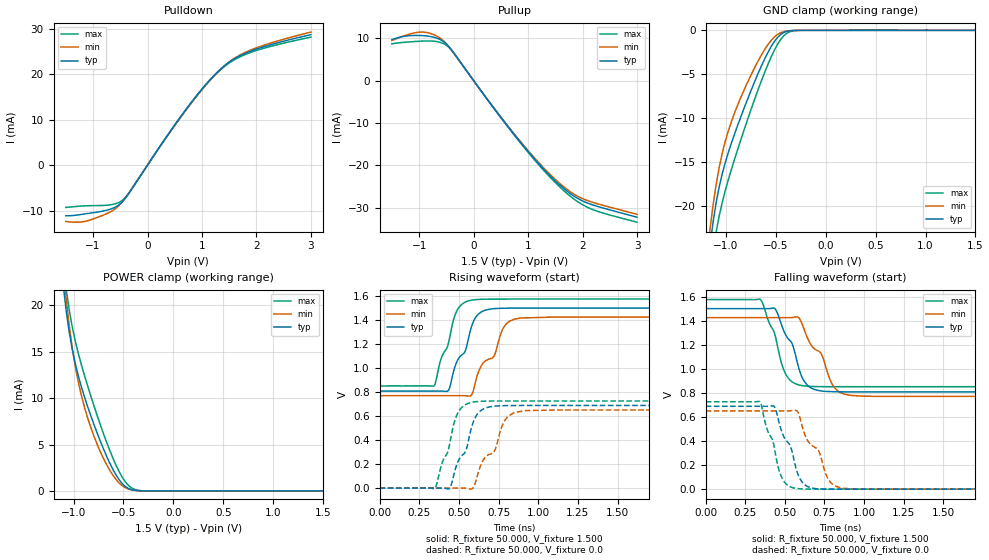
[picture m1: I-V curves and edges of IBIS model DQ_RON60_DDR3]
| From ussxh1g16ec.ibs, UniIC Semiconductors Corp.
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|   Model DQ_RON60_DDR3
[Model] DQ_RON60_DDR3
Model_type I/O
Vinl =  0.615V
Vinh =  0.885V
Vmeas =  0.750V
Rref =  50.000
Vref =  0.750V
C_comp   1.232pF   1.219pF   1.235pF
[Model Spec]
Vinh   0.885V   0.847V   0.922V
Vinl   0.615V   0.577V   0.652V
Vmeas   0.750V   0.712V   0.787V
Vref   0.750V   0.712V   0.787V
Rref   50.000   NA   NA
[Temperature Range]   25.000   95.000   0.0
[Voltage Range]   1.500V   1.425V   1.575V
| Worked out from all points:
|   slope of the pulldown table from 0 to 0.225 V, typ, clamps not added: 55.6 ohm
|   slope of the pullup table from 0 to 0.225 V, typ, clamps not added: 56.8 ohm
|   GND clamp passes 1 mA (typ) near -0.49 V on its own axis
|   POWER clamp passes 1 mA (typ) near -0.53 V on its own axis
|   rising waveform, R_fixture 50.000, V_fixture 1.500: 20-80 % time 122ps typ, 159ps min, 101ps max; typ from 0.808 V to 1.5 V
|   rising waveform, R_fixture 50.000, V_fixture 0.0: 20-80 % time 117ps typ, 151ps min, 98.5ps max; typ from 0 V to 0.688 V
|   falling waveform, R_fixture 50.000, V_fixture 1.500: 20-80 % time 123ps typ, 157ps min, 104ps max; typ from 1.5 V to 0.808 V
|   falling waveform, R_fixture 50.000, V_fixture 0.0: 20-80 % time 115ps typ, 148ps min, 95.5ps max; typ from 0.688 V to 0 V
[Pulldown]
|Voltage   I(typ)   I(min)   I(max)
-1.5V     -11.15mA   -12.39mA   -9.29mA
-1.224V   -10.85mA   -12.51mA   -9.004mA
-948mV    -10.37mA   -11.62mA   -8.896mA
-626mV    -9.419mA   -9.874mA   -8.605mA
-442mV    -7.812mA   -7.785mA   -7.561mA
-304mV    -5.522mA   -5.433mA   -5.531mA
340mV     6.066mA    5.969mA    6.085mA
800mV     13.71mA    13.56mA    13.69mA
1.168V    19.03mA    18.93mA    18.92mA
1.49V     22.55mA    22.6mA     22.35mA
1.996V    25.49mA    25.77mA    25.19mA
3V        28.67mA    29.24mA    28.12mA
[Pullup]
|Voltage   I(typ)   I(min)   I(max)
-1.5V     9.689mA    9.449mA    8.684mA
-1.14V    10.61mA    11.09mA    9.161mA
-910mV    10.58mA    11.42mA    9.33mA
-680mV    10.03mA    10.53mA    9.208mA
-496mV    8.577mA    8.63mA     8.283mA
-358mV    6.405mA    6.362mA    6.41mA
746mV     -12.72mA   -12.56mA   -12.85mA
1.16V     -19.08mA   -18.83mA   -19.32mA
1.528V    -23.99mA   -23.63mA   -24.4mA
1.804V    -26.9mA    -26.45mA   -27.55mA
2.08V     -28.81mA   -28.23mA   -29.79mA
3V        -32.21mA   -31.53mA   -33.38mA
[GND_clamp]
|Voltage   I(typ)   I(min)   I(max)
-1.5V     -77.15mA   -73.99mA   -82.95mA
-1.159V   -24.58mA   -22.75mA   -28.09mA
-1.128V   -21.88mA   -19.96mA   -25.29mA
-1.097V   -19.64mA   -17.59mA   -23mA
-1.066V   -17.82mA   -15.61mA   -21.13mA
-1.004V   -15mA      -12.58mA   -18.19mA
-880mV    -10.79mA   -8.48mA    -13.52mA
-632mV    -3.776mA   -2.594mA   -5.41mA
-477mV    -756.2uA   -431.9uA   -1.507mA
-384mV    -106.6uA   -66.16uA   -298.8uA
-291mV    -7.441uA   -6.674uA   -23.65uA
1.5V      0A         0A         0A
[POWER_clamp]
|Voltage   I(typ)   I(min)   I(max)
-1.5V     91.1mA     92.64mA    94.45mA
-1.104V   22.28mA    23.97mA    24.53mA
-1.073V   19.41mA    20.63mA    21.7mA
-1.042V   17.07mA    17.76mA    19.43mA
-980mV    13.62mA    13.3mA     16.05mA
-918mV    11.11mA    10.16mA    13.48mA
-856mV    9.013mA    7.787mA    11.23mA
-670mV    3.78mA     2.864mA    5.289mA
-577mV    1.775mA    1.269mA    2.836mA
-484mV    502.3uA    362.1uA    1.023mA
-298mV    5.274uA    7.672uA    13.48uA
1.5V      0A         0A         0A
[Ramp]
| variable   typ   min   max
dV/dt_r   0.413/0.117n   0.390/0.151n   0.436/98.657p
dV/dt_f   0.415/0.123n   0.393/0.157n   0.434/0.104n
R_load = 50.000
[Rising Waveform]
R_fixture= 50.000
V_fixture= 1.500
V_fixture_min= 1.425
V_fixture_max= 1.575
|time   V(typ)   V(min)   V(max)
0s        808mV      770.4mV    851.1mV
342ps     808.1mV    770.4mV    851.2mV
436ps     818.5mV    770.4mV    1.221V
489ps     1.059V     770.5mV    1.483V
539ps     1.14V      769.7mV    1.549V
576ps     1.331V     771.7mV    1.565V
653ps     1.476V     1.043V     1.574V
722ps     1.495V     1.101V     1.575V
848ps     1.5V       1.407V     1.575V
3ns       1.5V       1.425V     1.575V
[Rising Waveform]
R_fixture= 50.000
V_fixture= 0.0
V_fixture_min= 0.0
V_fixture_max= 0.0
|time   V(typ)   V(min)   V(max)
0s        174.5nV    711.1nV    276.3nV
346ps     -21.92uV   10.29uV    -5.042mV
442ps     220.1uV    -12.14uV   371.2mV
498ps     233.1mV    204.9uV    638mV
546ps     320.6mV    -543.7uV   699.2mV
586ps     534.9mV    -3.305mV   715.8mV
662ps     664.4mV    251mV      724.3mV
718ps     681.6mV    295.6mV    725.5mV
850ps     688mV      630mV      725.8mV
3ns       688.4mV    650.7mV    725.9mV
[Falling Waveform]
R_fixture= 50.000
V_fixture= 1.500
V_fixture_min= 1.425
V_fixture_max= 1.575
|time   V(typ)   V(min)   V(max)
0s        1.5V       1.425V     1.575V
344ps     1.5V       1.425V     1.577V
445ps     1.485V     1.425V     1.24V
511ps     1.267V     1.425V     942.3mV
552ps     1.187V     1.427V     885.8mV
603ps     946.2mV    1.391V     861.6mV
730ps     815.9mV    1.125V     851.7mV
797ps     809.9mV    875.8mV    851.3mV
882ps     808.3mV    787.1mV    851.2mV
3ns       808mV      770.4mV    851.2mV
[Falling Waveform]
R_fixture= 50.000
V_fixture= 0.0
V_fixture_min= 0.0
V_fixture_max= 0.0
|time   V(typ)   V(min)   V(max)
0s        688.4mV    650.7mV    725.9mV
341ps     688.4mV    650.6mV    727.1mV
434ps     684.7mV    650.6mV    339.9mV
481ps     472.5mV    650.5mV    94.12mV
561ps     222mV      654.8mV    8.52mV
644ps     20.98mV    402.3mV    691.4uV
714ps     2.688mV    316.6mV    81.15uV
780ps     383.3uV    70.26mV    11.03uV
864ps     31.35uV    7.026mV    1.28uV
3ns       348.6nV    799nV      444.5nV
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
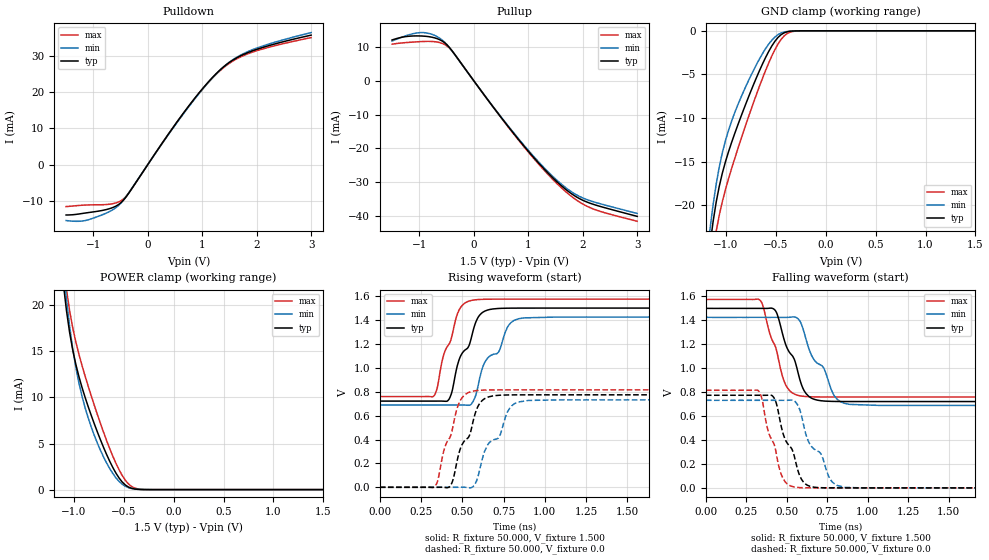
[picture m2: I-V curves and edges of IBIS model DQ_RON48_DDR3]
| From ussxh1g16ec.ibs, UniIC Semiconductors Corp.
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|   Model DQ_RON48_DDR3
[Model] DQ_RON48_DDR3
Model_type I/O
Vinl =  0.615V
Vinh =  0.885V
Vmeas =  0.750V
Rref =  50.000
Vref =  0.750V
C_comp   1.232pF   1.219pF   1.235pF
[Model Spec]
Vinh   0.885V   0.847V   0.922V
Vinl   0.615V   0.577V   0.652V
Vmeas   0.750V   0.712V   0.787V
Vref   0.750V   0.712V   0.787V
Rref   50.000   NA   NA
[Temperature Range]   25.000   95.000   0.0
[Voltage Range]   1.500V   1.425V   1.575V
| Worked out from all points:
|   slope of the pulldown table from 0 to 0.225 V, typ, clamps not added: 44.5 ohm
|   slope of the pullup table from 0 to 0.225 V, typ, clamps not added: 45.5 ohm
|   GND clamp passes 1 mA (typ) near -0.49 V on its own axis
|   POWER clamp passes 1 mA (typ) near -0.53 V on its own axis
|   rising waveform, R_fixture 50.000, V_fixture 1.500: 20-80 % time 123ps typ, 162ps min, 101ps max; typ from 0.721 V to 1.5 V
|   rising waveform, R_fixture 50.000, V_fixture 0.0: 20-80 % time 120ps typ, 155ps min, 99.7ps max; typ from 0 V to 0.774 V
|   falling waveform, R_fixture 50.000, V_fixture 1.500: 20-80 % time 124ps typ, 159ps min, 103ps max; typ from 1.5 V to 0.721 V
|   falling waveform, R_fixture 50.000, V_fixture 0.0: 20-80 % time 117ps typ, 151ps min, 95.1ps max; typ from 0.774 V to 0 V
[Pulldown]
|Voltage   I(typ)   I(min)   I(max)
-1.5V     -13.93mA   -15.46mA   -11.6mA
-1.224V   -13.56mA   -15.63mA   -11.25mA
-948mV    -12.96mA   -14.51mA   -11.12mA
-626mV    -11.77mA   -12.34mA   -10.75mA
-442mV    -9.758mA   -9.724mA   -9.445mA
-304mV    -6.897mA   -6.786mA   -6.908mA
340mV     7.577mA    7.456mA    7.6mA
800mV     17.13mA    16.94mA    17.1mA
1.168V    23.78mA    23.65mA    23.63mA
1.49V     28.17mA    28.23mA    27.92mA
1.996V    31.84mA    32.19mA    31.47mA
3V        35.8mA     36.51mA    35.12mA
[Pullup]
|Voltage   I(typ)   I(min)   I(max)
-1.5V     12.11mA    11.8mA     10.85mA
-1.14V    13.26mA    13.86mA    11.45mA
-910mV    13.22mA    14.27mA    11.66mA
-680mV    12.53mA    13.15mA    11.5mA
-496mV    10.71mA    10.78mA    10.35mA
-358mV    7.998mA    7.944mA    8.005mA
746mV     -15.88mA   -15.69mA   -16.04mA
1.16V     -23.82mA   -23.51mA   -24.13mA
1.528V    -29.95mA   -29.51mA   -30.47mA
1.804V    -33.59mA   -33.02mA   -34.4mA
2.08V     -35.96mA   -35.24mA   -37.19mA
3V        -40.2mA    -39.34mA   -41.66mA
[GND_clamp]
|Voltage   I(typ)   I(min)   I(max)
-1.5V     -77.15mA   -73.99mA   -82.95mA
-1.159V   -24.58mA   -22.75mA   -28.09mA
-1.128V   -21.88mA   -19.96mA   -25.29mA
-1.097V   -19.64mA   -17.59mA   -23mA
-1.066V   -17.82mA   -15.61mA   -21.13mA
-1.004V   -15mA      -12.58mA   -18.19mA
-880mV    -10.79mA   -8.48mA    -13.52mA
-632mV    -3.776mA   -2.594mA   -5.41mA
-477mV    -756.2uA   -431.9uA   -1.507mA
-384mV    -106.6uA   -66.16uA   -298.8uA
-291mV    -7.441uA   -6.674uA   -23.65uA
1.5V      0A         0A         0A
[POWER_clamp]
|Voltage   I(typ)   I(min)   I(max)
-1.5V     91.1mA     92.64mA    94.45mA
-1.104V   22.28mA    23.97mA    24.53mA
-1.073V   19.41mA    20.63mA    21.7mA
-1.042V   17.07mA    17.76mA    19.43mA
-980mV    13.62mA    13.3mA     16.05mA
-918mV    11.11mA    10.16mA    13.48mA
-856mV    9.013mA    7.787mA    11.23mA
-670mV    3.78mA     2.864mA    5.289mA
-577mV    1.775mA    1.269mA    2.836mA
-484mV    502.3uA    362.1uA    1.023mA
-298mV    5.274uA    7.672uA    13.48uA
1.5V      0A         0A         0A
[Ramp]
| variable   typ   min   max
dV/dt_r   0.464/0.120n   0.439/0.155n   0.489/99.767p
dV/dt_f   0.467/0.124n   0.442/0.159n   0.489/0.103n
R_load = 50.000
[Rising Waveform]
R_fixture= 50.000
V_fixture= 1.500
V_fixture_min= 1.425
V_fixture_max= 1.575
|time   V(typ)   V(min)   V(max)
0s        721.4mV    688.7mV    759.4mV
330ps     721.4mV    688.7mV    767.8mV
387ps     720.8mV    688.7mV    1.109V
419ps     736.3mV    688.7mV    1.198V
485ps     1.085V     689mV      1.496V
565ps     1.309V     717.6mV    1.567V
637ps     1.475V     1.049V     1.574V
720ps     1.497V     1.132V     1.575V
843ps     1.5V       1.411V     1.575V
3ns       1.5V       1.425V     1.575V
[Rising Waveform]
R_fixture= 50.000
V_fixture= 0.0
V_fixture_min= 0.0
V_fixture_max= 0.0
|time   V(typ)   V(min)   V(max)
0s        156.4nV    636.5nV    247.4nV
334ps     -30.04uV   10.7uV     7.104mV
393ps     -1.019mV   21.26uV    330.9mV
433ps     26.25mV    -20.36uV   447.2mV
485ps     311.5mV    344.5uV    720.1mV
565ps     551mV      5.918mV    805mV
636ps     742.5mV    305mV      814.1mV
718ps     769.7mV    412.2mV    815.5mV
840ps     773.7mV    713.8mV    815.7mV
3ns       774mV      731.8mV    815.7mV
[Falling Waveform]
R_fixture= 50.000
V_fixture= 1.500
V_fixture_min= 1.425
V_fixture_max= 1.575
|time   V(typ)   V(min)   V(max)
0s        1.5V       1.425V     1.575V
338ps     1.5V       1.425V     1.564V
435ps     1.469V     1.425V     1.158V
494ps     1.195V     1.425V     859.1mV
579ps     913.6mV    1.398V     770.1mV
651ps     751mV      1.112V     761mV
730ps     725.8mV    997.8mV    759.6mV
795ps     722.3mV    767mV      759.4mV
854ps     721.6mV    707.5mV    759.4mV
3ns       721.4mV    688.7mV    759.4mV
[Falling Waveform]
R_fixture= 50.000
V_fixture= 0.0
V_fixture_min= 0.0
V_fixture_max= 0.0
|time   V(typ)   V(min)   V(max)
0s        774mV      731.8mV    815.7mV
329ps     773.9mV    731.8mV    804.4mV
423ps     747.6mV    731.8mV    359.4mV
477ps     453.7mV    731.5mV    78.05mV
541ps     292.2mV    732.6mV    8.925mV
624ps     24.57mV    422mV      522uV
711ps     1.384mV    284.7mV    25.46uV
771ps     187.2uV    66.57mV    3.498uV
859ps     10.1uV     4.525mV    521nV
3ns       261.9nV    757.2nV    334.3nV
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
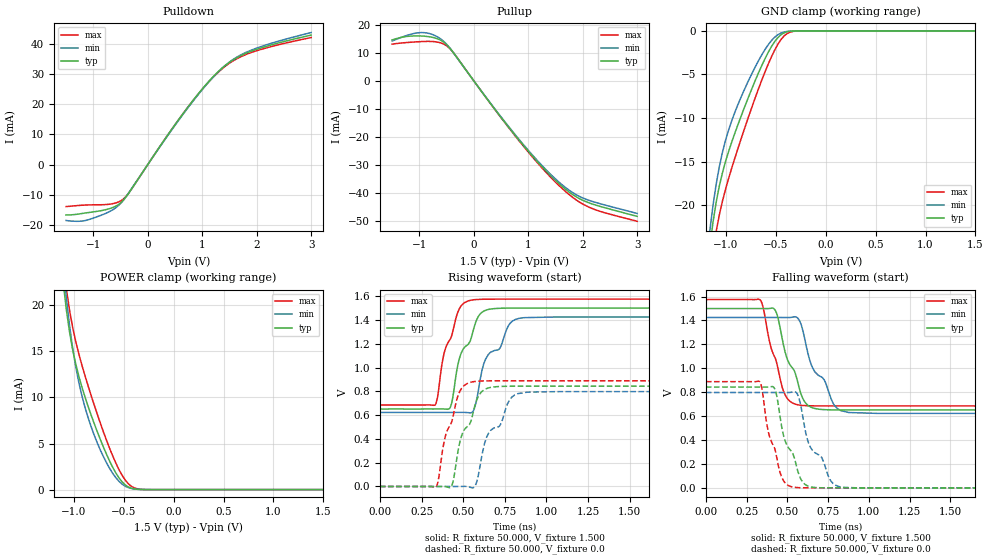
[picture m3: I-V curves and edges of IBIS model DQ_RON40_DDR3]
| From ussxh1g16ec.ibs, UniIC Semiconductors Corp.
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|   Model DQ_RON40_DDR3
[Model] DQ_RON40_DDR3
Model_type I/O
Vinl =  0.615V
Vinh =  0.885V
Vmeas =  0.750V
Rref =  50.000
Vref =  0.750V
C_comp   1.232pF   1.219pF   1.235pF
[Model Spec]
Vinh   0.885V   0.847V   0.922V
Vinl   0.615V   0.577V   0.652V
Vmeas   0.750V   0.712V   0.787V
Vref   0.750V   0.712V   0.787V
Rref   50.000   NA   NA
[Temperature Range]   25.000   95.000   0.0
[Voltage Range]   1.500V   1.425V   1.575V
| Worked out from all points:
|   slope of the pulldown table from 0 to 0.225 V, typ, clamps not added: 37.1 ohm
|   slope of the pullup table from 0 to 0.225 V, typ, clamps not added: 38 ohm
|   GND clamp passes 1 mA (typ) near -0.49 V on its own axis
|   POWER clamp passes 1 mA (typ) near -0.53 V on its own axis
|   rising waveform, R_fixture 50.000, V_fixture 1.500: 20-80 % time 118ps typ, 159ps min, 96.3ps max; typ from 0.651 V to 1.5 V
|   rising waveform, R_fixture 50.000, V_fixture 0.0: 20-80 % time 115ps typ, 152ps min, 94.3ps max; typ from 0 V to 0.843 V
|   falling waveform, R_fixture 50.000, V_fixture 1.500: 20-80 % time 119ps typ, 155ps min, 97.6ps max; typ from 1.5 V to 0.651 V
|   falling waveform, R_fixture 50.000, V_fixture 0.0: 20-80 % time 112ps typ, 147ps min, 89.6ps max; typ from 0.843 V to 0 V
[Pulldown]
|Voltage   I(typ)   I(min)   I(max)
-1.5V     -16.71mA   -18.54mA   -13.92mA
-1.224V   -16.26mA   -18.75mA   -13.49mA
-948mV    -15.55mA   -17.41mA   -13.34mA
-626mV    -14.12mA   -14.8mA    -12.9mA
-442mV    -11.7mA    -11.66mA   -11.33mA
-304mV    -8.268mA   -8.136mA   -8.282mA
340mV     9.085mA    8.939mA    9.112mA
800mV     20.54mA    20.31mA    20.51mA
1.168V    28.51mA    28.36mA    28.34mA
1.49V     33.78mA    33.85mA    33.48mA
1.996V    38.18mA    38.59mA    37.74mA
3V        42.92mA    43.77mA    42.11mA
[Pullup]
|Voltage   I(typ)   I(min)   I(max)
-1.5V     14.53mA    14.14mA    13.02mA
-1.14V    15.91mA    16.63mA    13.73mA
-910mV    15.87mA    17.12mA    13.99mA
-680mV    15.02mA    15.77mA    13.8mA
-496mV    12.85mA    12.92mA    12.41mA
-358mV    9.588mA    9.523mA    9.597mA
746mV     -19.04mA   -18.81mA   -19.23mA
1.16V     -28.56mA   -28.18mA   -28.93mA
1.528V    -35.91mA   -35.37mA   -36.53mA
1.804V    -40.27mA   -39.58mA   -41.24mA
2.08V     -43.11mA   -42.23mA   -44.59mA
3V        -48.17mA   -47.14mA   -49.93mA
[GND_clamp]
|Voltage   I(typ)   I(min)   I(max)
-1.5V     -77.15mA   -73.99mA   -82.95mA
-1.159V   -24.58mA   -22.75mA   -28.09mA
-1.128V   -21.88mA   -19.96mA   -25.29mA
-1.097V   -19.64mA   -17.59mA   -23mA
-1.066V   -17.82mA   -15.61mA   -21.13mA
-1.004V   -15mA      -12.58mA   -18.19mA
-880mV    -10.79mA   -8.48mA    -13.52mA
-632mV    -3.776mA   -2.594mA   -5.41mA
-477mV    -756.2uA   -431.9uA   -1.507mA
-384mV    -106.6uA   -66.16uA   -298.8uA
-291mV    -7.441uA   -6.674uA   -23.65uA
1.5V      0A         0A         0A
[POWER_clamp]
|Voltage   I(typ)   I(min)   I(max)
-1.5V     91.1mA     92.64mA    94.45mA
-1.104V   22.28mA    23.97mA    24.53mA
-1.073V   19.41mA    20.63mA    21.7mA
-1.042V   17.07mA    17.76mA    19.43mA
-980mV    13.62mA    13.3mA     16.05mA
-918mV    11.11mA    10.16mA    13.48mA
-856mV    9.013mA    7.787mA    11.23mA
-670mV    3.78mA     2.864mA    5.289mA
-577mV    1.775mA    1.269mA    2.836mA
-484mV    502.3uA    362.1uA    1.023mA
-298mV    5.274uA    7.672uA    13.48uA
1.5V      0A         0A         0A
[Ramp]
| variable   typ   min   max
dV/dt_r   0.506/0.115n   0.479/0.152n   0.533/94.273p
dV/dt_f   0.509/0.119n   0.481/0.155n   0.534/97.244p
R_load = 50.000
[Rising Waveform]
R_fixture= 50.000
V_fixture= 1.500
V_fixture_min= 1.425
V_fixture_max= 1.575
|time   V(typ)   V(min)   V(max)
0s        651.3mV    622.6mV    685.3mV
333ps     651.4mV    622.6mV    687.3mV
386ps     651.4mV    622.6mV    1.122V
421ps     661.1mV    622.6mV    1.235V
484ps     1.106V     622.9mV    1.511V
548ps     1.247V     619.7mV    1.566V
574ps     1.375V     687.5mV    1.571V
634ps     1.481V     1.069V     1.574V
836ps     1.5V       1.413V     1.575V
3ns       1.5V       1.425V     1.575V
[Rising Waveform]
R_fixture= 50.000
V_fixture= 0.0
V_fixture_min= 0.0
V_fixture_max= 0.0
|time   V(typ)   V(min)   V(max)
0s        141.7nV    576.3nV    224.2nV
338ps     -18.65uV   14.37uV    -4.278mV
387ps     560.9uV    28.12uV    386.2mV
430ps     2.625mV    -17.08uV   538.5mV
484ps     395.7mV    415uV      810.3mV
555ps     590.9mV    -11.54mV   879.2mV
581ps     724.9mV    36.69mV    884.1mV
640ps     822.7mV    411.8mV    887.7mV
828ps     843.1mV    780.4mV    888.4mV
3ns       843.3mV    797.6mV    888.4mV
[Falling Waveform]
R_fixture= 50.000
V_fixture= 1.500
V_fixture_min= 1.425
V_fixture_max= 1.575
|time   V(typ)   V(min)   V(max)
0s        1.5V       1.425V     1.575V
333ps     1.5V       1.425V     1.572V
428ps     1.479V     1.425V     1.077V
486ps     1.137V     1.425V     778.8mV
562ps     893.4mV    1.422V     695.5mV
600ps     733.9mV    1.287V     688.7mV
656ps     668.7mV    1V         685.9mV
789ps     651.9mV    689.5mV    685.3mV
877ps     651.4mV    630mV      685.3mV
3ns       651.3mV    622.6mV    685.3mV
[Falling Waveform]
R_fixture= 50.000
V_fixture= 0.0
V_fixture_min= 0.0
V_fixture_max= 0.0
|time   V(typ)   V(min)   V(max)
0s        843.3mV    797.6mV    888.5mV
330ps     843.2mV    797.6mV    888mV
385ps     843.5mV    797.6mV    458.5mV
423ps     826.1mV    797.6mV    325.8mV
479ps     424.3mV    797.2mV    54.38mV
533ps     287.5mV    801.4mV    7.075mV
572ps     106.4mV    746mV      1.595mV
613ps     24.54mV    458.8mV    330.9uV
817ps     13.72uV    10.69mV    472.5nV
3ns       233nV      662.5nV    288.9nV
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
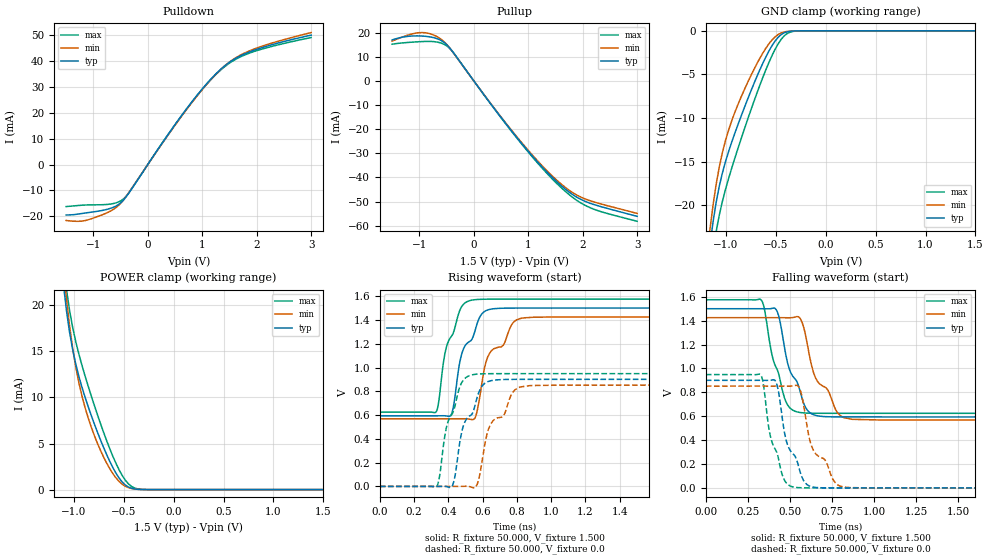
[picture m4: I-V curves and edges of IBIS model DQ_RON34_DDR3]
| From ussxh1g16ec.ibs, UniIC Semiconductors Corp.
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|   Model DQ_RON34_DDR3
[Model] DQ_RON34_DDR3
Model_type I/O
Vinl =  0.615V
Vinh =  0.885V
Vmeas =  0.750V
Rref =  50.000
Vref =  0.750V
C_comp   1.232pF   1.219pF   1.235pF
[Model Spec]
Vinh   0.885V   0.847V   0.922V
Vinl   0.615V   0.577V   0.652V
Vmeas   0.750V   0.712V   0.787V
Vref   0.750V   0.712V   0.787V
Rref   50.000   NA   NA
[Temperature Range]   25.000   95.000   0.0
[Voltage Range]   1.500V   1.425V   1.575V
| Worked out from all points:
|   slope of the pulldown table from 0 to 0.225 V, typ, clamps not added: 31.9 ohm
|   slope of the pullup table from 0 to 0.225 V, typ, clamps not added: 32.6 ohm
|   GND clamp passes 1 mA (typ) near -0.49 V on its own axis
|   POWER clamp passes 1 mA (typ) near -0.53 V on its own axis
|   rising waveform, R_fixture 50.000, V_fixture 1.500: 20-80 % time 117ps typ, 158ps min, 94.5ps max; typ from 0.594 V to 1.5 V
|   rising waveform, R_fixture 50.000, V_fixture 0.0: 20-80 % time 114ps typ, 152ps min, 93.1ps max; typ from 0 V to 0.9 V
|   falling waveform, R_fixture 50.000, V_fixture 1.500: 20-80 % time 116ps typ, 152ps min, 93.7ps max; typ from 1.5 V to 0.594 V
|   falling waveform, R_fixture 50.000, V_fixture 0.0: 20-80 % time 110ps typ, 146ps min, 87.7ps max; typ from 0.9 V to 0 V
[Pulldown]
|Voltage   I(typ)   I(min)   I(max)
-1.5V     -19.49mA   -21.6mA    -16.23mA
-1.224V   -18.96mA   -21.87mA   -15.73mA
-948mV    -18.13mA   -20.29mA   -15.55mA
-626mV    -16.46mA   -17.25mA   -15.04mA
-442mV    -13.64mA   -13.59mA   -13.21mA
-304mV    -9.636mA   -9.482mA   -9.652mA
340mV     10.59mA    10.42mA    10.62mA
800mV     23.94mA    23.67mA    23.9mA
1.168V    33.23mA    33.05mA    33.03mA
1.49V     39.38mA    39.46mA    39.04mA
1.996V    44.51mA    44.98mA    44mA
3V        50.02mA    51.01mA    49.08mA
[Pullup]
|Voltage   I(typ)   I(min)   I(max)
-1.5V     16.95mA    16.48mA    15.19mA
-1.14V    18.56mA    19.4mA     16.02mA
-910mV    18.5mA     19.96mA    16.31mA
-680mV    17.52mA    18.39mA    16.09mA
-496mV    14.97mA    15.06mA    14.46mA
-358mV    11.17mA    11.1mA     11.18mA
746mV     -22.19mA   -21.92mA   -22.41mA
1.16V     -33.28mA   -32.84mA   -33.71mA
1.528V    -41.84mA   -41.22mA   -42.57mA
1.804V    -46.92mA   -46.11mA   -48.06mA
2.08V     -50.22mA   -49.19mA   -51.95mA
3V        -56.11mA   -54.9mA    -58.16mA
[GND_clamp]
|Voltage   I(typ)   I(min)   I(max)
-1.5V     -77.15mA   -73.99mA   -82.95mA
-1.159V   -24.58mA   -22.75mA   -28.09mA
-1.128V   -21.88mA   -19.96mA   -25.29mA
-1.097V   -19.64mA   -17.59mA   -23mA
-1.066V   -17.82mA   -15.61mA   -21.13mA
-1.004V   -15mA      -12.58mA   -18.19mA
-880mV    -10.79mA   -8.48mA    -13.52mA
-632mV    -3.776mA   -2.594mA   -5.41mA
-477mV    -756.2uA   -431.9uA   -1.507mA
-384mV    -106.6uA   -66.16uA   -298.8uA
-291mV    -7.441uA   -6.674uA   -23.65uA
1.5V      0A         0A         0A
[POWER_clamp]
|Voltage   I(typ)   I(min)   I(max)
-1.5V     91.1mA     92.64mA    94.45mA
-1.104V   22.28mA    23.97mA    24.53mA
-1.073V   19.41mA    20.63mA    21.7mA
-1.042V   17.07mA    17.76mA    19.43mA
-980mV    13.62mA    13.3mA     16.05mA
-918mV    11.11mA    10.16mA    13.48mA
-856mV    9.013mA    7.787mA    11.23mA
-670mV    3.78mA     2.864mA    5.289mA
-577mV    1.775mA    1.269mA    2.836mA
-484mV    502.3uA    362.1uA    1.023mA
-298mV    5.274uA    7.672uA    13.48uA
1.5V      0A         0A         0A
[Ramp]
| variable   typ   min   max
dV/dt_r   0.540/0.114n   0.511/0.153n   0.569/93.104p
dV/dt_f   0.544/0.116n   0.514/0.152n   0.570/93.649p
R_load = 50.000
[Rising Waveform]
R_fixture= 50.000
V_fixture= 1.500
V_fixture_min= 1.425
V_fixture_max= 1.575
|time   V(typ)   V(min)   V(max)
0s        593.7mV    568.1mV    624.3mV
326ps     593.7mV    568.1mV    622.5mV
378ps     594.1mV    568.1mV    1.103V
418ps     605.9mV    568.1mV    1.262V
474ps     1.092V     568.4mV    1.503V
531ps     1.225V     563.8mV    1.565V
561ps     1.336V     594.2mV    1.571V
630ps     1.484V     1.089V     1.575V
821ps     1.5V       1.412V     1.575V
3ns       1.5V       1.425V     1.575V
[Rising Waveform]
R_fixture= 50.000
V_fixture= 0.0
V_fixture_min= 0.0
V_fixture_max= 0.0
|time   V(typ)   V(min)   V(max)
0s        129.7nV    526.6nV    205.1nV
333ps     -36.51uV   15.67uV    773.9uV
387ps     -197uV     35.4uV     485.4mV
426ps     12.61mV    -24.03uV   619.3mV
480ps     470mV      552.4uV    878.3mV
540ps     612.9mV    -8.92mV    938.6mV
576ps     784.3mV    51.42mV    945.2mV
647ps     888.4mV    524.2mV    948.1mV
819ps     900.3mV    835.9mV    948.4mV
3ns       900.5mV    852mV      948.4mV
[Falling Waveform]
R_fixture= 50.000
V_fixture= 1.500
V_fixture_min= 1.425
V_fixture_max= 1.575
|time   V(typ)   V(min)   V(max)
0s        1.5V       1.425V     1.575V
332ps     1.5V       1.425V     1.568V
389ps     1.501V     1.425V     1.139V
422ps     1.482V     1.425V     995.2mV
495ps     998.9mV    1.424V     676.1mV
551ps     853.6mV    1.432V     633.2mV
595ps     666.6mV    1.261V     626.6mV
653ps     606.5mV    916.6mV    624.7mV
820ps     593.9mV    588.4mV    624.3mV
3ns       593.7mV    568.1mV    624.3mV
[Falling Waveform]
R_fixture= 50.000
V_fixture= 0.0
V_fixture_min= 0.0
V_fixture_max= 0.0
|time   V(typ)   V(min)   V(max)
0s        900.5mV    852mV      948.4mV
326ps     900.4mV    852mV      946.7mV
381ps     900.8mV    851.9mV    447.5mV
416ps     888mV      852mV      313.6mV
473ps     422.9mV    851.5mV    50.75mV
521ps     280.6mV    854.6mV    6.923mV
562ps     125.4mV    815.1mV    1.265mV
642ps     5.371mV    305.4mV    43.25uV
799ps     10.09uV    13.61mV    448nV
3ns       160.5nV    586.1nV    315.1nV
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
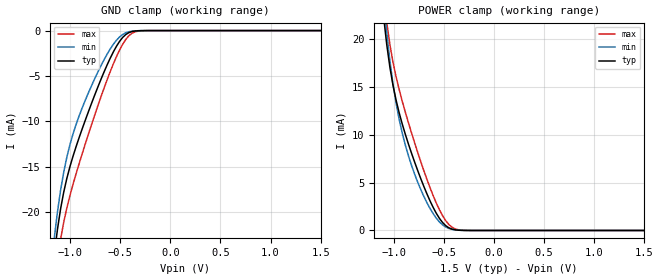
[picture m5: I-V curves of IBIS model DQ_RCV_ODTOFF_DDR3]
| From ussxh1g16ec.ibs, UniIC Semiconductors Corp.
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|   Model DQ_RCV_ODTOFF_DDR3
[Model] DQ_RCV_ODTOFF_DDR3
Model_type Input
Vinl =  0.615V
Vinh =  0.885V
C_comp   1.232pF   1.219pF   1.235pF
[Model Spec]
Vinh   0.885V   0.847V   0.922V
Vinl   0.615V   0.577V   0.652V
[Temperature Range]   25.000   95.000   0.0
[Voltage Range]   1.500V   1.425V   1.575V
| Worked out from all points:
|   GND clamp passes 1 mA (typ) near -0.49 V on its own axis
|   POWER clamp passes 1 mA (typ) near -0.53 V on its own axis
[GND_clamp]
|Voltage   I(typ)   I(min)   I(max)
-1.5V     -77.15mA   -73.99mA   -82.95mA
-1.159V   -24.58mA   -22.75mA   -28.09mA
-1.128V   -21.88mA   -19.96mA   -25.29mA
-1.097V   -19.64mA   -17.59mA   -23mA
-1.066V   -17.82mA   -15.61mA   -21.13mA
-1.004V   -15mA      -12.58mA   -18.19mA
-880mV    -10.79mA   -8.48mA    -13.52mA
-632mV    -3.776mA   -2.594mA   -5.41mA
-477mV    -756.2uA   -431.9uA   -1.507mA
-384mV    -106.6uA   -66.16uA   -298.8uA
-291mV    -7.441uA   -6.674uA   -23.65uA
1.5V      0A         0A         0A
[POWER_clamp]
|Voltage   I(typ)   I(min)   I(max)
-1.5V     91.1mA     92.64mA    94.45mA
-1.104V   22.28mA    23.97mA    24.53mA
-1.073V   19.41mA    20.63mA    21.7mA
-1.042V   17.07mA    17.76mA    19.43mA
-980mV    13.62mA    13.3mA     16.05mA
-918mV    11.11mA    10.16mA    13.48mA
-856mV    9.013mA    7.787mA    11.23mA
-670mV    3.78mA     2.864mA    5.289mA
-577mV    1.775mA    1.269mA    2.836mA
-484mV    502.3uA    362.1uA    1.023mA
-298mV    5.274uA    7.672uA    13.48uA
1.5V      0A         0A         0A
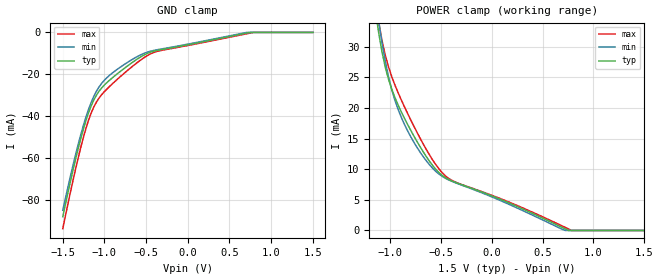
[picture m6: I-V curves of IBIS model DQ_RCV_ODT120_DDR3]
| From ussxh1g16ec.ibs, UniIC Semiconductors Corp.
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|   Model DQ_RCV_ODT120_DDR3
[Model] DQ_RCV_ODT120_DDR3
Model_type Input
Vinl =  0.615V
Vinh =  0.885V
C_comp   1.232pF   1.219pF   1.235pF
[Model Spec]
Vinh   0.885V   0.847V   0.922V
Vinl   0.615V   0.577V   0.652V
[Temperature Range]   25.000   95.000   0.0
[Voltage Range]   1.500V   1.425V   1.575V
[GND_clamp]
|Voltage   I(typ)   I(min)   I(max)
-1.5V     -87.98mA   -84.92mA   -93.67mA
-1.376V   -65.54mA   -63.2mA    -70.41mA
-1.283V   -50.54mA   -48.68mA   -54.71mA
-1.19V    -38.27mA   -36.64mA   -41.81mA
-1.128V   -32.28mA   -30.55mA   -35.62mA
-1.066V   -28.14mA   -26.1mA    -31.4mA
-973mV    -24.05mA   -21.7mA    -27.13mA
-632mV    -13.41mA   -12.11mA   -15.19mA
-477mV    -9.882mA   -9.319mA   -10.88mA
-353mV    -8.483mA   -8.172mA   -8.911mA
763mV     0A         0A         -201.5uA
1.5V      0A         0A         0A
[POWER_clamp]
|Voltage   I(typ)   I(min)   I(max)
-1.5V     100.7mA    102.3mA    103.7mA
-1.135V   35.28mA    37.51mA    37.09mA
-1.104V   31.83mA    33.71mA    33.64mA
-1.073V   28.93mA    30.36mA    30.8mA
-1.011V   24.65mA    25.04mA    26.66mA
-949mV    21.71mA    21.27mA    23.75mA
-887mV    19.38mA    18.5mA     21.34mA
-701mV    13.65mA    12.77mA    15.04mA
-484mV    8.973mA    8.826mA    9.419mA
-360mV    7.872mA    7.821mA    7.933mA
725mV     235.4uA    0A         488.5uA
1.5V      0A         0A         0A
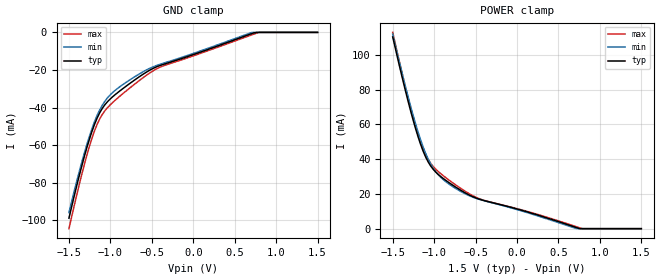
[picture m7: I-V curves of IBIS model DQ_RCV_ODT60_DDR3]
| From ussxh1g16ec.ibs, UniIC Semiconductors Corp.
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|   Model DQ_RCV_ODT60_DDR3
[Model] DQ_RCV_ODT60_DDR3
Model_type Input
Vinl =  0.615V
Vinh =  0.885V
C_comp   1.232pF   1.219pF   1.235pF
[Model Spec]
Vinh   0.885V   0.847V   0.922V
Vinl   0.615V   0.577V   0.652V
[Temperature Range]   25.000   95.000   0.0
[Voltage Range]   1.500V   1.425V   1.575V
[GND_clamp]
|Voltage   I(typ)   I(min)   I(max)
-1.5V     -98.81mA   -95.83mA   -104.4mA
-1.314V   -65.94mA   -64.08mA   -70.23mA
-1.221V   -52.48mA   -51.01mA   -56.1mA
-1.159V   -45.46mA   -44.01mA   -48.8mA
-1.097V   -40.36mA   -38.66mA   -43.59mA
-1.004V   -35.48mA   -33.3mA    -38.61mA
-725mV    -25.87mA   -24.11mA   -28.14mA
-539mV    -20.45mA   -19.4mA    -22mA
-384mV    -17.35mA   -16.73mA   -18.18mA
701mV     -713.4uA   -113.1uA   -1.389mA
794mV     0A         0A         0A
1.5V      0A         0A         0A
[POWER_clamp]
|Voltage   I(typ)   I(min)   I(max)
-1.5V     110.3mA    111.9mA    112.9mA
-1.29V    68.86mA    71.51mA    70.74mA
-1.197V   53.33mA    56.05mA    54.83mA
-1.135V   44.85mA    47.25mA    46.23mA
-1.073V   38.46mA    40.1mA     39.91mA
-1.011V   34.13mA    34.75mA    35.74mA
-856mV    27.66mA    26.9mA     29.2mA
-639mV    20.97mA    20.4mA     21.93mA
-453mV    16.93mA    16.81mA    17.19mA
725mV     470.7uA    0A         977uA
787mV     0A         0A         0A
1.5V      0A         0A         0A
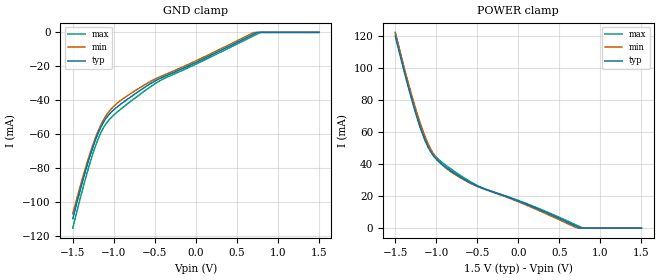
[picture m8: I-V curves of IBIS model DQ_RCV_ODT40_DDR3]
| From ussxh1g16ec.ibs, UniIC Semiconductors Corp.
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|   Model DQ_RCV_ODT40_DDR3
[Model] DQ_RCV_ODT40_DDR3
Model_type Input
Vinl =  0.615V
Vinh =  0.885V
C_comp   1.232pF   1.219pF   1.235pF
[Model Spec]
Vinh   0.885V   0.847V   0.922V
Vinl   0.615V   0.577V   0.652V
[Temperature Range]   25.000   95.000   0.0
[Voltage Range]   1.500V   1.425V   1.575V
[GND_clamp]
|Voltage   I(typ)   I(min)   I(max)
-1.5V     -109.6mA   -106.7mA   -115.1mA
-1.314V   -76.53mA   -74.83mA   -80.69mA
-1.252V   -67.15mA   -65.75mA   -70.86mA
-1.19V    -59.17mA   -57.93mA   -62.53mA
-1.128V   -53.03mA   -51.65mA   -56.22mA
-1.066V   -48.73mA   -46.99mA   -51.88mA
-880mV    -40.95mA   -38.78mA   -43.78mA
-601mV    -31.63mA   -30.19mA   -33.62mA
-415mV    -26.58mA   -25.64mA   -27.83mA
701mV     -1.066mA   -167.7uA   -2.078mA
794mV     0A         0A         0A
1.5V      0A         0A         0A
[POWER_clamp]
|Voltage   I(typ)   I(min)   I(max)
-1.5V     119.8mA    121.5mA    122.1mA
-1.29V    78.46mA    81.2mA     79.92mA
-1.166V   58.41mA    61.19mA    59.4mA
-1.104V   50.89mA    53.17mA    51.86mA
-1.042V   45.55mA    46.9mA     46.67mA
-887mV    38.08mA    37.67mA    39.33mA
-670mV    30.84mA    30.31mA    31.67mA
-453mV    25.21mA    25.07mA    25.43mA
105mV     14.82mA    14.21mA    15.19mA
725mV     706uA      0A         1.463mA
787mV     0A         0A         0A
1.5V      0A         0A         0A
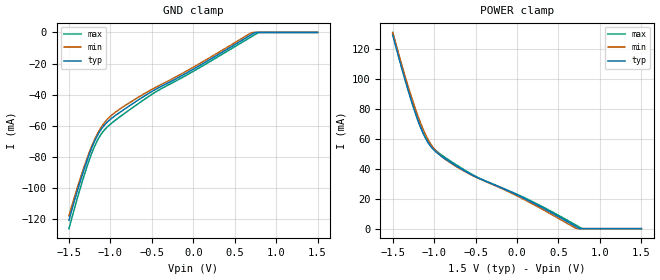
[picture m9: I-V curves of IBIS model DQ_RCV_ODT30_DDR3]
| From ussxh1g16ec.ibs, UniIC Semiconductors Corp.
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|   Model DQ_RCV_ODT30_DDR3
[Model] DQ_RCV_ODT30_DDR3
Model_type Input
Vinl =  0.615V
Vinh =  0.885V
C_comp   1.232pF   1.219pF   1.235pF
[Model Spec]
Vinh   0.885V   0.847V   0.922V
Vinl   0.615V   0.577V   0.652V
[Temperature Range]   25.000   95.000   0.0
[Voltage Range]   1.500V   1.425V   1.575V
[GND_clamp]
|Voltage   I(typ)   I(min)   I(max)
-1.5V     -120.5mA   -117.7mA   -125.9mA
-1.345V   -92.36mA   -90.6mA    -96.64mA
-1.221V   -73.53mA   -72.43mA   -76.96mA
-1.128V   -63.48mA   -62.29mA   -66.61mA
-1.066V   -59.1mA    -57.52mA   -62.21mA
-973mV    -54.65mA   -52.59mA   -57.69mA
-756mV    -46.61mA   -44.67mA   -49.17mA
-446mV    -36.3mA    -35.05mA   -37.96mA
-12mV     -23.99mA   -22.73mA   -25.33mA
701mV     -1.428mA   -226.9uA   -2.779mA
794mV     0A         0A         0A
1.5V      0A         0A         0A
[POWER_clamp]
|Voltage   I(typ)   I(min)   I(max)
-1.5V     129.5mA    131.1mA    131.4mA
-1.29V    88.13mA    90.97mA    89.17mA
-1.166V   68.05mA    70.99mA    68.6mA
-1.104V   60.49mA    62.96mA    61.04mA
-1.042V   55.11mA    56.69mA    55.82mA
-980mV    51.45mA    52.1mA     52.32mA
-887mV    47.49mA    47.32mA    48.39mA
-484mV    34.36mA    34.18mA    34.61mA
105mV     19.79mA    18.97mA    20.28mA
725mV     939uA      0A         1.952mA
787mV     0A         0A         0A
1.5V      0A         0A         0A
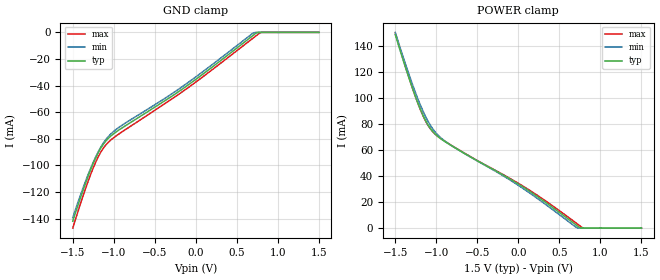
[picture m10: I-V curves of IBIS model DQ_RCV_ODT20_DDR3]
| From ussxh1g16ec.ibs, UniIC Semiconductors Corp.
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|   Model DQ_RCV_ODT20_DDR3
[Model] DQ_RCV_ODT20_DDR3
Model_type Input
Vinl =  0.615V
Vinh =  0.885V
C_comp   1.232pF   1.219pF   1.235pF
[Model Spec]
Vinh   0.885V   0.847V   0.922V
Vinl   0.615V   0.577V   0.652V
[Temperature Range]   25.000   95.000   0.0
[Voltage Range]   1.500V   1.425V   1.575V
[GND_clamp]
|Voltage   I(typ)   I(min)   I(max)
-1.5V     -142mA     -139.3mA   -147.2mA
-1.345V   -113.6mA   -112.1mA   -117.6mA
-1.283V   -103.4mA   -102.4mA   -107mA
-1.221V   -94.43mA   -93.69mA   -97.66mA
-1.128V   -84.14mA   -83.3mA    -87.12mA
-1.066V   -79.6mA    -78.31mA   -82.62mA
-1.004V   -76.31mA   -74.58mA   -79.34mA
-136mV    -41.39mA   -39.51mA   -43.42mA
701mV     -2.131mA   -333uA     -4.151mA
732mV     -645.7uA   0A         -2.672mA
794mV     0A         0A         0A
1.5V      0A         0A         0A
[POWER_clamp]
|Voltage   I(typ)   I(min)   I(max)
-1.5V     148.6mA    150.3mA    149.9mA
-1.321V   113mA      115.9mA    113.4mA
-1.197V   91.69mA    94.99mA    91.47mA
-1.104V   79.54mA    82.4mA     79.24mA
-1.042V   74.06mA    76.09mA    73.96mA
-980mV    70.3mA     71.43mA    70.4mA
-763mV    61.38mA    61.3mA     61.57mA
43mV      32.14mA    31.05mA    32.77mA
353mV     18.82mA    17.21mA    19.97mA
725mV     1.411mA    0A         2.926mA
787mV     0A         0A         0A
1.5V      0A         0A         0A
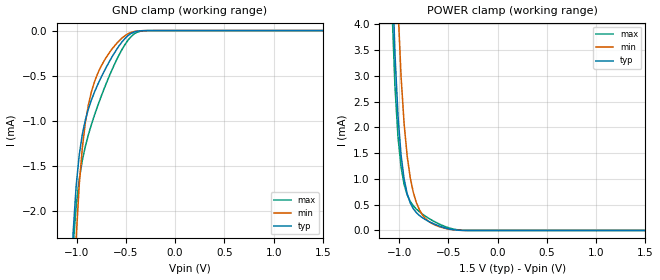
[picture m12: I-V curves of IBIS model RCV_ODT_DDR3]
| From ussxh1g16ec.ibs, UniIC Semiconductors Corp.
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|   Model RCV_ODT_DDR3
[Model] RCV_ODT_DDR3
Model_type Input
Vinl =  0.615V
Vinh =  0.885V
C_comp   0.902pF   0.902pF   0.902pF
[Model Spec]
Vinh   0.885V   0.847V   0.922V
Vinl   0.615V   0.577V   0.652V
[Temperature Range]   25.000   95.000   0.0
[Voltage Range]   1.500V   1.425V   1.575V
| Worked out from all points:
|   GND clamp passes 1 mA (typ) near -0.91 V on its own axis
|   POWER clamp passes 1 mA (typ) near -0.95 V on its own axis
[GND_clamp]
|Voltage   I(typ)   I(min)   I(max)
-1.5V     -69.37mA   -68.94mA   -70.54mA
-1.035V   -2.238mA   -3.131mA   -2.386mA
-1.004V   -1.714mA   -2.288mA   -1.938mA
-973mV    -1.376mA   -1.704mA   -1.645mA
-942mV    -1.149mA   -1.3mA     -1.439mA
-911mV    -989uA     -1.019mA   -1.282mA
-849mV    -766.8uA   -675.4uA   -1.038mA
-725mV    -460.8uA   -342.9uA   -655.8uA
-508mV    -86.33uA   -55.84uA   -152.8uA
-415mV    -15.24uA   -10.47uA   -35.87uA
-322mV    -1.052uA   -1.065uA   -2.81uA
1.5V      0A         0A         0A
[POWER_clamp]
|Voltage   I(typ)   I(min)   I(max)
-1.5V     89.87mA    92.1mA     89.8mA
-1.073V   5.259mA    8.664mA    4.371mA
-1.042V   3.423mA    6.175mA    2.788mA
-1.011V   2.217mA    4.314mA    1.81mA
-980mV    1.46mA     2.983mA    1.229mA
-949mV    995.9uA    2.065mA    890.2uA
-918mV    711.2uA    1.443mA    689.3uA
-856mV    421.6uA    739uA      479.2uA
-763mV    246.6uA    302.1uA    317.2uA
-608mV    97.8uA     83.77uA    139.2uA
-360mV    2.014uA    2.213uA    4.534uA
1.5V      0A         0A         0A
